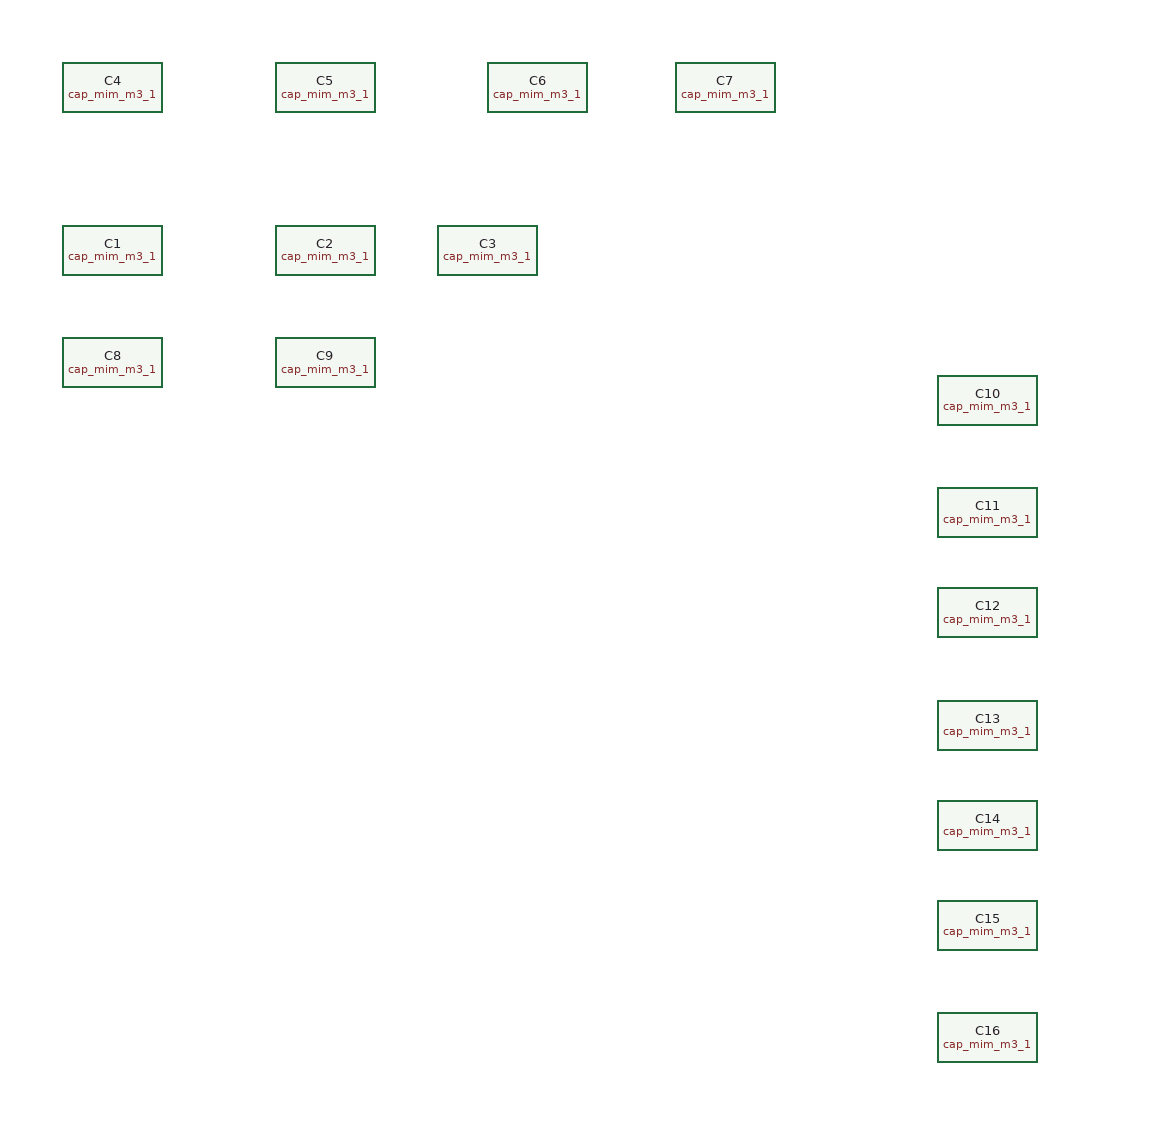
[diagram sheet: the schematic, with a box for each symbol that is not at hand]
v {xschem version=3.4.5 file_version=1.2
}
G {}
K {}
V {}
S {}
E {}
C {sky130_fd_pr/cap_mim_m3_1.sym} 70 -80 0 0 {name=C1 model=cap_mim_m3_1 W=9.7 L=8.3 MF=1 spiceprefix=X}
C {sky130_fd_pr/cap_mim_m3_1.sym} 240 -80 0 0 {name=C2 model=cap_mim_m3_1 W=4 L=3.8 MF=1 spiceprefix=X}
C {sky130_fd_pr/cap_mim_m3_1.sym} 370 -80 0 0 {name=C3 model=cap_mim_m3_1 W=3.2 L=2.3 MF=1 spiceprefix=X}
C {sky130_fd_pr/cap_mim_m3_1.sym} 70 -210 0 0 {name=C4 model=cap_mim_m3_1 W=30 L=30 MF=823 spiceprefix=X}
C {sky130_fd_pr/cap_mim_m3_1.sym} 240 -210 0 0 {name=C5 model=cap_mim_m3_1 W=30 L=30 MF=21400 spiceprefix=X}
C {sky130_fd_pr/cap_mim_m3_1.sym} 410 -210 0 0 {name=C6 model=cap_mim_m3_1 W=30 L=30 MF=37 spiceprefix=X}
C {sky130_fd_pr/cap_mim_m3_1.sym} 560 -210 0 0 {name=C7 model=cap_mim_m3_1 W=30 L=30 MF=178 spiceprefix=X}
C {sky130_fd_pr/cap_mim_m3_1.sym} 70 10 0 0 {name=C8 model=cap_mim_m3_1 W=26 L=25.2 MF=3 spiceprefix=X}
C {sky130_fd_pr/cap_mim_m3_1.sym} 240 10 0 0 {name=C9 model=cap_mim_m3_1 W=30 L=28.8 MF=12 spiceprefix=X}
C {sky130_fd_pr/cap_mim_m3_1.sym} 770 40 0 0 {name=C10 model=cap_mim_m3_1 W=770 L=30 MF=1 spiceprefix=X}
C {sky130_fd_pr/cap_mim_m3_1.sym} 770 130 0 0 {name=C11 model=cap_mim_m3_1 W=77 L=30 MF=1 spiceprefix=X}
C {sky130_fd_pr/cap_mim_m3_1.sym} 770 210 0 0 {name=C12 model=cap_mim_m3_1 W=150 L=30 MF=1 spiceprefix=X}
C {sky130_fd_pr/cap_mim_m3_1.sym} 770 300 0 0 {name=C13 model=cap_mim_m3_1 W=150 L=150 MF=1 spiceprefix=X}
C {sky130_fd_pr/cap_mim_m3_1.sym} 770 380 0 0 {name=C14 model=cap_mim_m3_1 W=150 L=15 MF=1 spiceprefix=X}
C {sky130_fd_pr/cap_mim_m3_1.sym} 770 460 0 0 {name=C15 model=cap_mim_m3_1 W=67 L=67 MF=1 spiceprefix=X}
C {sky130_fd_pr/cap_mim_m3_1.sym} 770 550 0 0 {name=C16 model=cap_mim_m3_1 W=48 L=48 MF=1 spiceprefix=X}
